###############################################################
#  Generated by:      Cadence Innovus 20.13-s083_1
#  OS:                Linux x86_64(Host ID rice-503-20-north)
#  Generated on:      Thu Sep  1 19:14:34 2022
#  Design:            bgr_top
#  Command:           write_lef_abstract -5.8 -extractBlockObs /home/users/lyt1314/ee372/aloe-sky130/bgr_top/interface/gen-0-id-0/bgr_top.lef
###############################################################

VERSION 5.8 ;

BUSBITCHARS "[]" ;
DIVIDERCHAR "/" ;

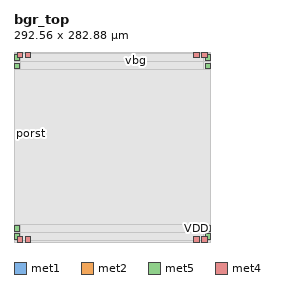
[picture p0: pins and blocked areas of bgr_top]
MACRO bgr_top
  CLASS BLOCK ;
  SIZE 292.560000 BY 282.880000 ;
  FOREIGN bgr_top 0.000000 0.000000 ;
  ORIGIN 0 0 ;
  SYMMETRY X Y R90 ;
  PIN porst
    DIRECTION INOUT ;
    USE SIGNAL ;
    PORT
      LAYER met1 ;
        RECT 0.000000 161.600000 0.595000 161.740000 ;
    END
  END porst
  PIN vbg
    DIRECTION INOUT ;
    USE SIGNAL ;
    PORT
      LAYER met2 ;
        RECT 180.940000 282.395000 181.080000 282.880000 ;
    END
  END vbg
  PIN VDD
    DIRECTION INOUT ;
    USE POWER ;
    PORT
      LAYER met5 ;
        RECT 284.400000 258.240000 292.560000 266.400000 ;
    END
    PORT
      LAYER met5 ;
        RECT 0.000000 258.240000 8.160000 266.400000 ;
    END
    PORT
      LAYER met5 ;
        RECT 284.400000 16.320000 292.560000 24.480000 ;
    END
    PORT
      LAYER met5 ;
        RECT 0.000000 16.320000 8.160000 24.480000 ;
    END
    PORT
      LAYER met4 ;
        RECT 267.280000 274.720000 275.440000 282.880000 ;
    END
    PORT
      LAYER met4 ;
        RECT 267.280000 0.000000 275.440000 8.160000 ;
    END
    PORT
      LAYER met4 ;
        RECT 16.740000 274.720000 24.900000 282.880000 ;
    END
    PORT
      LAYER met4 ;
        RECT 16.740000 0.000000 24.900000 8.160000 ;
    END
  END VDD
  PIN VSS
    DIRECTION INOUT ;
    USE GROUND ;
    PORT
      LAYER met5 ;
        RECT 284.400000 270.480000 292.560000 278.640000 ;
    END
    PORT
      LAYER met5 ;
        RECT 0.000000 270.480000 8.160000 278.640000 ;
    END
    PORT
      LAYER met5 ;
        RECT 284.400000 4.080000 292.560000 12.240000 ;
    END
    PORT
      LAYER met5 ;
        RECT 0.000000 4.080000 8.160000 12.240000 ;
    END
    PORT
      LAYER met4 ;
        RECT 279.520000 274.720000 287.680000 282.880000 ;
    END
    PORT
      LAYER met4 ;
        RECT 279.520000 0.000000 287.680000 8.160000 ;
    END
    PORT
      LAYER met4 ;
        RECT 4.500000 274.720000 12.660000 282.880000 ;
    END
    PORT
      LAYER met4 ;
        RECT 4.500000 0.000000 12.660000 8.160000 ;
    END
  END VSS
  OBS
    LAYER li1 ;
      RECT 0.000000 0.000000 292.560000 282.880000 ;
    LAYER met1 ;
      RECT 0.000000 162.020000 292.560000 282.880000 ;
      RECT 0.875000 161.320000 292.560000 162.020000 ;
      RECT 0.000000 0.000000 292.560000 161.320000 ;
    LAYER met2 ;
      RECT 181.360000 282.115000 292.560000 282.880000 ;
      RECT 0.000000 282.115000 180.660000 282.880000 ;
      RECT 0.000000 0.000000 292.560000 282.115000 ;
    LAYER met3 ;
      RECT 0.000000 0.000000 292.560000 282.880000 ;
    LAYER met4 ;
      RECT 288.080000 274.320000 292.560000 282.880000 ;
      RECT 275.840000 274.320000 279.120000 282.880000 ;
      RECT 25.300000 274.320000 266.880000 282.880000 ;
      RECT 13.060000 274.320000 16.340000 282.880000 ;
      RECT 0.000000 274.320000 4.100000 282.880000 ;
      RECT 0.000000 8.560000 292.560000 274.320000 ;
      RECT 288.080000 0.000000 292.560000 8.560000 ;
      RECT 275.840000 0.000000 279.120000 8.560000 ;
      RECT 25.300000 0.000000 266.880000 8.560000 ;
      RECT 13.060000 0.000000 16.340000 8.560000 ;
      RECT 0.000000 0.000000 4.100000 8.560000 ;
    LAYER met5 ;
      RECT 0.000000 280.240000 292.560000 282.880000 ;
      RECT 9.760000 268.880000 282.800000 280.240000 ;
      RECT 0.000000 268.000000 292.560000 268.880000 ;
      RECT 9.760000 256.640000 282.800000 268.000000 ;
      RECT 0.000000 26.080000 292.560000 256.640000 ;
      RECT 9.760000 14.720000 282.800000 26.080000 ;
      RECT 0.000000 13.840000 292.560000 14.720000 ;
      RECT 9.760000 2.480000 282.800000 13.840000 ;
      RECT 0.000000 0.000000 292.560000 2.480000 ;
  END
END bgr_top

END LIBRARY
